VERSION 5.7 ;
BUSBITCHARS "[]" ;
DIVIDERCHAR "/" ;
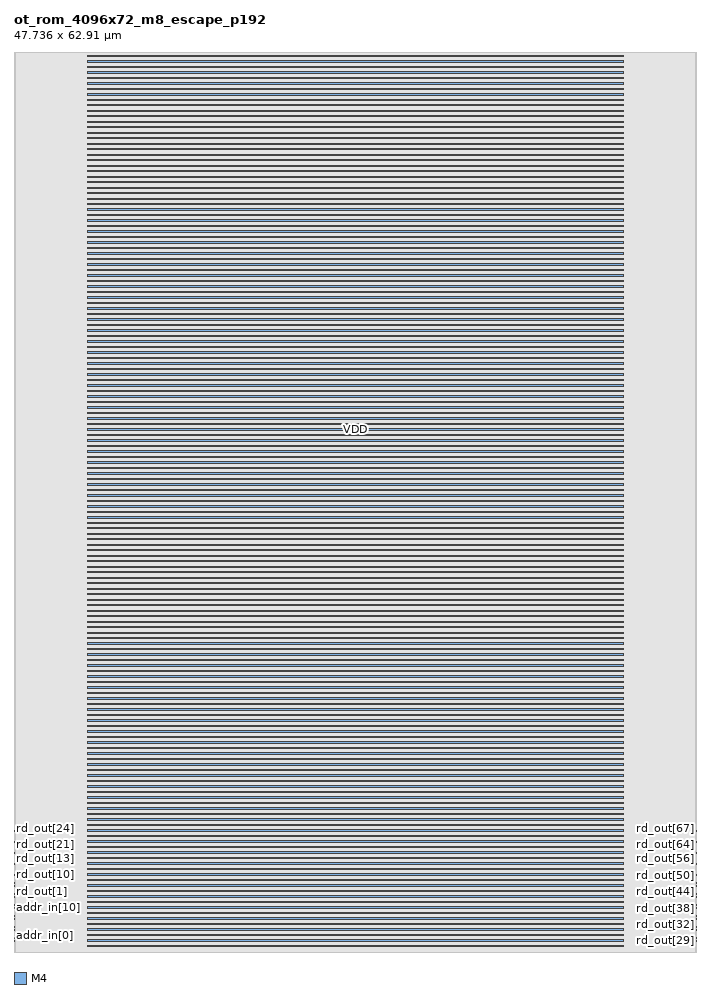
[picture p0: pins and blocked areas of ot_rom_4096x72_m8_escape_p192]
MACRO ot_rom_4096x72_m8_escape_p192
  SIZE 47.736 BY 62.910 ;
  CLASS BLOCK ;
  PIN clk
    DIRECTION INPUT ;
    USE CLOCK ;
    PORT
      LAYER M4 ;
      RECT 0.000 0.768 0.024 0.792 ;
    END
  END clk
  PIN ce_in
    DIRECTION INPUT ;
    USE SIGNAL ;
    PORT
      LAYER M4 ;
      RECT 0.000 0.960 0.024 0.984 ;
    END
  END ce_in
  PIN addr_in[0]
    DIRECTION INPUT ;
    USE SIGNAL ;
    PORT
      LAYER M4 ;
      RECT 0.000 1.152 0.024 1.176 ;
    END
  END addr_in[0]
  PIN addr_in[1]
    DIRECTION INPUT ;
    USE SIGNAL ;
    PORT
      LAYER M4 ;
      RECT 0.000 1.344 0.024 1.368 ;
    END
  END addr_in[1]
  PIN addr_in[2]
    DIRECTION INPUT ;
    USE SIGNAL ;
    PORT
      LAYER M4 ;
      RECT 0.000 1.536 0.024 1.560 ;
    END
  END addr_in[2]
  PIN addr_in[3]
    DIRECTION INPUT ;
    USE SIGNAL ;
    PORT
      LAYER M4 ;
      RECT 0.000 1.728 0.024 1.752 ;
    END
  END addr_in[3]
  PIN addr_in[4]
    DIRECTION INPUT ;
    USE SIGNAL ;
    PORT
      LAYER M4 ;
      RECT 0.000 1.920 0.024 1.944 ;
    END
  END addr_in[4]
  PIN addr_in[5]
    DIRECTION INPUT ;
    USE SIGNAL ;
    PORT
      LAYER M4 ;
      RECT 0.000 2.112 0.024 2.136 ;
    END
  END addr_in[5]
  PIN addr_in[6]
    DIRECTION INPUT ;
    USE SIGNAL ;
    PORT
      LAYER M4 ;
      RECT 0.000 2.304 0.024 2.328 ;
    END
  END addr_in[6]
  PIN addr_in[7]
    DIRECTION INPUT ;
    USE SIGNAL ;
    PORT
      LAYER M4 ;
      RECT 0.000 2.496 0.024 2.520 ;
    END
  END addr_in[7]
  PIN addr_in[8]
    DIRECTION INPUT ;
    USE SIGNAL ;
    PORT
      LAYER M4 ;
      RECT 0.000 2.688 0.024 2.712 ;
    END
  END addr_in[8]
  PIN addr_in[9]
    DIRECTION INPUT ;
    USE SIGNAL ;
    PORT
      LAYER M4 ;
      RECT 0.000 2.880 0.024 2.904 ;
    END
  END addr_in[9]
  PIN addr_in[10]
    DIRECTION INPUT ;
    USE SIGNAL ;
    PORT
      LAYER M4 ;
      RECT 0.000 3.072 0.024 3.096 ;
    END
  END addr_in[10]
  PIN addr_in[11]
    DIRECTION INPUT ;
    USE SIGNAL ;
    PORT
      LAYER M4 ;
      RECT 0.000 3.264 0.024 3.288 ;
    END
  END addr_in[11]
  PIN rd_out[0]
    DIRECTION OUTPUT ;
    USE SIGNAL ;
    PORT
      LAYER M4 ;
      RECT 0.000 3.456 0.024 3.480 ;
    END
  END rd_out[0]
  PIN rd_out[1]
    DIRECTION OUTPUT ;
    USE SIGNAL ;
    PORT
      LAYER M4 ;
      RECT 0.000 3.648 0.024 3.672 ;
    END
  END rd_out[1]
  PIN rd_out[2]
    DIRECTION OUTPUT ;
    USE SIGNAL ;
    PORT
      LAYER M4 ;
      RECT 0.000 3.840 0.024 3.864 ;
    END
  END rd_out[2]
  PIN rd_out[3]
    DIRECTION OUTPUT ;
    USE SIGNAL ;
    PORT
      LAYER M4 ;
      RECT 0.000 4.032 0.024 4.056 ;
    END
  END rd_out[3]
  PIN rd_out[4]
    DIRECTION OUTPUT ;
    USE SIGNAL ;
    PORT
      LAYER M4 ;
      RECT 0.000 4.224 0.024 4.248 ;
    END
  END rd_out[4]
  PIN rd_out[5]
    DIRECTION OUTPUT ;
    USE SIGNAL ;
    PORT
      LAYER M4 ;
      RECT 0.000 4.416 0.024 4.440 ;
    END
  END rd_out[5]
  PIN rd_out[6]
    DIRECTION OUTPUT ;
    USE SIGNAL ;
    PORT
      LAYER M4 ;
      RECT 0.000 4.608 0.024 4.632 ;
    END
  END rd_out[6]
  PIN rd_out[7]
    DIRECTION OUTPUT ;
    USE SIGNAL ;
    PORT
      LAYER M4 ;
      RECT 0.000 4.800 0.024 4.824 ;
    END
  END rd_out[7]
  PIN rd_out[8]
    DIRECTION OUTPUT ;
    USE SIGNAL ;
    PORT
      LAYER M4 ;
      RECT 0.000 4.992 0.024 5.016 ;
    END
  END rd_out[8]
  PIN rd_out[9]
    DIRECTION OUTPUT ;
    USE SIGNAL ;
    PORT
      LAYER M4 ;
      RECT 0.000 5.184 0.024 5.208 ;
    END
  END rd_out[9]
  PIN rd_out[10]
    DIRECTION OUTPUT ;
    USE SIGNAL ;
    PORT
      LAYER M4 ;
      RECT 0.000 5.376 0.024 5.400 ;
    END
  END rd_out[10]
  PIN rd_out[11]
    DIRECTION OUTPUT ;
    USE SIGNAL ;
    PORT
      LAYER M4 ;
      RECT 0.000 5.568 0.024 5.592 ;
    END
  END rd_out[11]
  PIN rd_out[12]
    DIRECTION OUTPUT ;
    USE SIGNAL ;
    PORT
      LAYER M4 ;
      RECT 0.000 5.760 0.024 5.784 ;
    END
  END rd_out[12]
  PIN rd_out[13]
    DIRECTION OUTPUT ;
    USE SIGNAL ;
    PORT
      LAYER M4 ;
      RECT 0.000 5.952 0.024 5.976 ;
    END
  END rd_out[13]
  PIN rd_out[14]
    DIRECTION OUTPUT ;
    USE SIGNAL ;
    PORT
      LAYER M4 ;
      RECT 0.000 6.144 0.024 6.168 ;
    END
  END rd_out[14]
  PIN rd_out[15]
    DIRECTION OUTPUT ;
    USE SIGNAL ;
    PORT
      LAYER M4 ;
      RECT 0.000 6.336 0.024 6.360 ;
    END
  END rd_out[15]
  PIN rd_out[16]
    DIRECTION OUTPUT ;
    USE SIGNAL ;
    PORT
      LAYER M4 ;
      RECT 0.000 6.528 0.024 6.552 ;
    END
  END rd_out[16]
  PIN rd_out[17]
    DIRECTION OUTPUT ;
    USE SIGNAL ;
    PORT
      LAYER M4 ;
      RECT 0.000 6.720 0.024 6.744 ;
    END
  END rd_out[17]
  PIN rd_out[18]
    DIRECTION OUTPUT ;
    USE SIGNAL ;
    PORT
      LAYER M4 ;
      RECT 0.000 6.912 0.024 6.936 ;
    END
  END rd_out[18]
  PIN rd_out[19]
    DIRECTION OUTPUT ;
    USE SIGNAL ;
    PORT
      LAYER M4 ;
      RECT 0.000 7.104 0.024 7.128 ;
    END
  END rd_out[19]
  PIN rd_out[20]
    DIRECTION OUTPUT ;
    USE SIGNAL ;
    PORT
      LAYER M4 ;
      RECT 0.000 7.296 0.024 7.320 ;
    END
  END rd_out[20]
  PIN rd_out[21]
    DIRECTION OUTPUT ;
    USE SIGNAL ;
    PORT
      LAYER M4 ;
      RECT 0.000 7.488 0.024 7.512 ;
    END
  END rd_out[21]
  PIN rd_out[22]
    DIRECTION OUTPUT ;
    USE SIGNAL ;
    PORT
      LAYER M4 ;
      RECT 0.000 7.680 0.024 7.704 ;
    END
  END rd_out[22]
  PIN rd_out[23]
    DIRECTION OUTPUT ;
    USE SIGNAL ;
    PORT
      LAYER M4 ;
      RECT 0.000 7.872 0.024 7.896 ;
    END
  END rd_out[23]
  PIN rd_out[24]
    DIRECTION OUTPUT ;
    USE SIGNAL ;
    PORT
      LAYER M4 ;
      RECT 0.000 8.064 0.024 8.088 ;
    END
  END rd_out[24]
  PIN rd_out[25]
    DIRECTION OUTPUT ;
    USE SIGNAL ;
    PORT
      LAYER M4 ;
      RECT 0.000 8.256 0.024 8.280 ;
    END
  END rd_out[25]
  PIN rd_out[26]
    DIRECTION OUTPUT ;
    USE SIGNAL ;
    PORT
      LAYER M4 ;
      RECT 0.000 8.448 0.024 8.472 ;
    END
  END rd_out[26]
  PIN rd_out[27]
    DIRECTION OUTPUT ;
    USE SIGNAL ;
    PORT
      LAYER M4 ;
      RECT 0.000 8.640 0.024 8.664 ;
    END
  END rd_out[27]
  PIN rd_out[28]
    DIRECTION OUTPUT ;
    USE SIGNAL ;
    PORT
      LAYER M4 ;
      RECT 0.000 8.832 0.024 8.856 ;
    END
  END rd_out[28]
  PIN rd_out[29]
    DIRECTION OUTPUT ;
    USE SIGNAL ;
    PORT
      LAYER M4 ;
      RECT 47.712 0.768 47.736 0.792 ;
    END
  END rd_out[29]
  PIN rd_out[30]
    DIRECTION OUTPUT ;
    USE SIGNAL ;
    PORT
      LAYER M4 ;
      RECT 47.712 0.960 47.736 0.984 ;
    END
  END rd_out[30]
  PIN rd_out[31]
    DIRECTION OUTPUT ;
    USE SIGNAL ;
    PORT
      LAYER M4 ;
      RECT 47.712 1.152 47.736 1.176 ;
    END
  END rd_out[31]
  PIN rd_out[32]
    DIRECTION OUTPUT ;
    USE SIGNAL ;
    PORT
      LAYER M4 ;
      RECT 47.712 1.344 47.736 1.368 ;
    END
  END rd_out[32]
  PIN rd_out[33]
    DIRECTION OUTPUT ;
    USE SIGNAL ;
    PORT
      LAYER M4 ;
      RECT 47.712 1.536 47.736 1.560 ;
    END
  END rd_out[33]
  PIN rd_out[34]
    DIRECTION OUTPUT ;
    USE SIGNAL ;
    PORT
      LAYER M4 ;
      RECT 47.712 1.728 47.736 1.752 ;
    END
  END rd_out[34]
  PIN rd_out[35]
    DIRECTION OUTPUT ;
    USE SIGNAL ;
    PORT
      LAYER M4 ;
      RECT 47.712 1.920 47.736 1.944 ;
    END
  END rd_out[35]
  PIN rd_out[36]
    DIRECTION OUTPUT ;
    USE SIGNAL ;
    PORT
      LAYER M4 ;
      RECT 47.712 2.112 47.736 2.136 ;
    END
  END rd_out[36]
  PIN rd_out[37]
    DIRECTION OUTPUT ;
    USE SIGNAL ;
    PORT
      LAYER M4 ;
      RECT 47.712 2.304 47.736 2.328 ;
    END
  END rd_out[37]
  PIN rd_out[38]
    DIRECTION OUTPUT ;
    USE SIGNAL ;
    PORT
      LAYER M4 ;
      RECT 47.712 2.496 47.736 2.520 ;
    END
  END rd_out[38]
  PIN rd_out[39]
    DIRECTION OUTPUT ;
    USE SIGNAL ;
    PORT
      LAYER M4 ;
      RECT 47.712 2.688 47.736 2.712 ;
    END
  END rd_out[39]
  PIN rd_out[40]
    DIRECTION OUTPUT ;
    USE SIGNAL ;
    PORT
      LAYER M4 ;
      RECT 47.712 2.880 47.736 2.904 ;
    END
  END rd_out[40]
  PIN rd_out[41]
    DIRECTION OUTPUT ;
    USE SIGNAL ;
    PORT
      LAYER M4 ;
      RECT 47.712 3.072 47.736 3.096 ;
    END
  END rd_out[41]
  PIN rd_out[42]
    DIRECTION OUTPUT ;
    USE SIGNAL ;
    PORT
      LAYER M4 ;
      RECT 47.712 3.264 47.736 3.288 ;
    END
  END rd_out[42]
  PIN rd_out[43]
    DIRECTION OUTPUT ;
    USE SIGNAL ;
    PORT
      LAYER M4 ;
      RECT 47.712 3.456 47.736 3.480 ;
    END
  END rd_out[43]
  PIN rd_out[44]
    DIRECTION OUTPUT ;
    USE SIGNAL ;
    PORT
      LAYER M4 ;
      RECT 47.712 3.648 47.736 3.672 ;
    END
  END rd_out[44]
  PIN rd_out[45]
    DIRECTION OUTPUT ;
    USE SIGNAL ;
    PORT
      LAYER M4 ;
      RECT 47.712 3.840 47.736 3.864 ;
    END
  END rd_out[45]
  PIN rd_out[46]
    DIRECTION OUTPUT ;
    USE SIGNAL ;
    PORT
      LAYER M4 ;
      RECT 47.712 4.032 47.736 4.056 ;
    END
  END rd_out[46]
  PIN rd_out[47]
    DIRECTION OUTPUT ;
    USE SIGNAL ;
    PORT
      LAYER M4 ;
      RECT 47.712 4.224 47.736 4.248 ;
    END
  END rd_out[47]
  PIN rd_out[48]
    DIRECTION OUTPUT ;
    USE SIGNAL ;
    PORT
      LAYER M4 ;
      RECT 47.712 4.416 47.736 4.440 ;
    END
  END rd_out[48]
  PIN rd_out[49]
    DIRECTION OUTPUT ;
    USE SIGNAL ;
    PORT
      LAYER M4 ;
      RECT 47.712 4.608 47.736 4.632 ;
    END
  END rd_out[49]
  PIN rd_out[50]
    DIRECTION OUTPUT ;
    USE SIGNAL ;
    PORT
      LAYER M4 ;
      RECT 47.712 4.800 47.736 4.824 ;
    END
  END rd_out[50]
  PIN rd_out[51]
    DIRECTION OUTPUT ;
    USE SIGNAL ;
    PORT
      LAYER M4 ;
      RECT 47.712 4.992 47.736 5.016 ;
    END
  END rd_out[51]
  PIN rd_out[52]
    DIRECTION OUTPUT ;
    USE SIGNAL ;
    PORT
      LAYER M4 ;
      RECT 47.712 5.184 47.736 5.208 ;
    END
  END rd_out[52]
  PIN rd_out[53]
    DIRECTION OUTPUT ;
    USE SIGNAL ;
    PORT
      LAYER M4 ;
      RECT 47.712 5.376 47.736 5.400 ;
    END
  END rd_out[53]
  PIN rd_out[54]
    DIRECTION OUTPUT ;
    USE SIGNAL ;
    PORT
      LAYER M4 ;
      RECT 47.712 5.568 47.736 5.592 ;
    END
  END rd_out[54]
  PIN rd_out[55]
    DIRECTION OUTPUT ;
    USE SIGNAL ;
    PORT
      LAYER M4 ;
      RECT 47.712 5.760 47.736 5.784 ;
    END
  END rd_out[55]
  PIN rd_out[56]
    DIRECTION OUTPUT ;
    USE SIGNAL ;
    PORT
      LAYER M4 ;
      RECT 47.712 5.952 47.736 5.976 ;
    END
  END rd_out[56]
  PIN rd_out[57]
    DIRECTION OUTPUT ;
    USE SIGNAL ;
    PORT
      LAYER M4 ;
      RECT 47.712 6.144 47.736 6.168 ;
    END
  END rd_out[57]
  PIN rd_out[58]
    DIRECTION OUTPUT ;
    USE SIGNAL ;
    PORT
      LAYER M4 ;
      RECT 47.712 6.336 47.736 6.360 ;
    END
  END rd_out[58]
  PIN rd_out[59]
    DIRECTION OUTPUT ;
    USE SIGNAL ;
    PORT
      LAYER M4 ;
      RECT 47.712 6.528 47.736 6.552 ;
    END
  END rd_out[59]
  PIN rd_out[60]
    DIRECTION OUTPUT ;
    USE SIGNAL ;
    PORT
      LAYER M4 ;
      RECT 47.712 6.720 47.736 6.744 ;
    END
  END rd_out[60]
  PIN rd_out[61]
    DIRECTION OUTPUT ;
    USE SIGNAL ;
    PORT
      LAYER M4 ;
      RECT 47.712 6.912 47.736 6.936 ;
    END
  END rd_out[61]
  PIN rd_out[62]
    DIRECTION OUTPUT ;
    USE SIGNAL ;
    PORT
      LAYER M4 ;
      RECT 47.712 7.104 47.736 7.128 ;
    END
  END rd_out[62]
  PIN rd_out[63]
    DIRECTION OUTPUT ;
    USE SIGNAL ;
    PORT
      LAYER M4 ;
      RECT 47.712 7.296 47.736 7.320 ;
    END
  END rd_out[63]
  PIN rd_out[64]
    DIRECTION OUTPUT ;
    USE SIGNAL ;
    PORT
      LAYER M4 ;
      RECT 47.712 7.488 47.736 7.512 ;
    END
  END rd_out[64]
  PIN rd_out[65]
    DIRECTION OUTPUT ;
    USE SIGNAL ;
    PORT
      LAYER M4 ;
      RECT 47.712 7.680 47.736 7.704 ;
    END
  END rd_out[65]
  PIN rd_out[66]
    DIRECTION OUTPUT ;
    USE SIGNAL ;
    PORT
      LAYER M4 ;
      RECT 47.712 7.872 47.736 7.896 ;
    END
  END rd_out[66]
  PIN rd_out[67]
    DIRECTION OUTPUT ;
    USE SIGNAL ;
    PORT
      LAYER M4 ;
      RECT 47.712 8.064 47.736 8.088 ;
    END
  END rd_out[67]
  PIN rd_out[68]
    DIRECTION OUTPUT ;
    USE SIGNAL ;
    PORT
      LAYER M4 ;
      RECT 47.712 8.256 47.736 8.280 ;
    END
  END rd_out[68]
  PIN rd_out[69]
    DIRECTION OUTPUT ;
    USE SIGNAL ;
    PORT
      LAYER M4 ;
      RECT 47.712 8.448 47.736 8.472 ;
    END
  END rd_out[69]
  PIN rd_out[70]
    DIRECTION OUTPUT ;
    USE SIGNAL ;
    PORT
      LAYER M4 ;
      RECT 47.712 8.640 47.736 8.664 ;
    END
  END rd_out[70]
  PIN rd_out[71]
    DIRECTION OUTPUT ;
    USE SIGNAL ;
    PORT
      LAYER M4 ;
      RECT 47.712 8.832 47.736 8.856 ;
    END
  END rd_out[71]
  PIN VDD
    DIRECTION INOUT ;
    USE POWER ;
    PORT
      LAYER M4 ;
      RECT 5.160 0.384 42.576 0.480 ;
      RECT 5.160 1.152 42.576 1.248 ;
      RECT 5.160 1.920 42.576 2.016 ;
      RECT 5.160 2.688 42.576 2.784 ;
      RECT 5.160 3.456 42.576 3.552 ;
      RECT 5.160 4.224 42.576 4.320 ;
      RECT 5.160 4.992 42.576 5.088 ;
      RECT 5.160 5.760 42.576 5.856 ;
      RECT 5.160 6.528 42.576 6.624 ;
      RECT 5.160 7.296 42.576 7.392 ;
      RECT 5.160 8.064 42.576 8.160 ;
      RECT 5.160 8.832 42.576 8.928 ;
      RECT 5.160 9.600 42.576 9.696 ;
      RECT 5.160 10.368 42.576 10.464 ;
      RECT 5.160 11.136 42.576 11.232 ;
      RECT 5.160 11.904 42.576 12.000 ;
      RECT 5.160 12.672 42.576 12.768 ;
      RECT 5.160 13.440 42.576 13.536 ;
      RECT 5.160 14.208 42.576 14.304 ;
      RECT 5.160 14.976 42.576 15.072 ;
      RECT 5.160 15.744 42.576 15.840 ;
      RECT 5.160 16.512 42.576 16.608 ;
      RECT 5.160 17.280 42.576 17.376 ;
      RECT 5.160 18.048 42.576 18.144 ;
      RECT 5.160 18.816 42.576 18.912 ;
      RECT 5.160 19.584 42.576 19.680 ;
      RECT 5.160 20.352 42.576 20.448 ;
      RECT 5.160 21.120 42.576 21.216 ;
      RECT 5.160 21.888 42.576 21.984 ;
      RECT 5.160 22.656 42.576 22.752 ;
      RECT 5.160 23.424 42.576 23.520 ;
      RECT 5.160 24.192 42.576 24.288 ;
      RECT 5.160 24.960 42.576 25.056 ;
      RECT 5.160 25.728 42.576 25.824 ;
      RECT 5.160 26.496 42.576 26.592 ;
      RECT 5.160 27.264 42.576 27.360 ;
      RECT 5.160 28.032 42.576 28.128 ;
      RECT 5.160 28.800 42.576 28.896 ;
      RECT 5.160 29.568 42.576 29.664 ;
      RECT 5.160 30.336 42.576 30.432 ;
      RECT 5.160 31.104 42.576 31.200 ;
      RECT 5.160 31.872 42.576 31.968 ;
      RECT 5.160 32.640 42.576 32.736 ;
      RECT 5.160 33.408 42.576 33.504 ;
      RECT 5.160 34.176 42.576 34.272 ;
      RECT 5.160 34.944 42.576 35.040 ;
      RECT 5.160 35.712 42.576 35.808 ;
      RECT 5.160 36.480 42.576 36.576 ;
      RECT 5.160 37.248 42.576 37.344 ;
      RECT 5.160 38.016 42.576 38.112 ;
      RECT 5.160 38.784 42.576 38.880 ;
      RECT 5.160 39.552 42.576 39.648 ;
      RECT 5.160 40.320 42.576 40.416 ;
      RECT 5.160 41.088 42.576 41.184 ;
      RECT 5.160 41.856 42.576 41.952 ;
      RECT 5.160 42.624 42.576 42.720 ;
      RECT 5.160 43.392 42.576 43.488 ;
      RECT 5.160 44.160 42.576 44.256 ;
      RECT 5.160 44.928 42.576 45.024 ;
      RECT 5.160 45.696 42.576 45.792 ;
      RECT 5.160 46.464 42.576 46.560 ;
      RECT 5.160 47.232 42.576 47.328 ;
      RECT 5.160 48.000 42.576 48.096 ;
      RECT 5.160 48.768 42.576 48.864 ;
      RECT 5.160 49.536 42.576 49.632 ;
      RECT 5.160 50.304 42.576 50.400 ;
      RECT 5.160 51.072 42.576 51.168 ;
      RECT 5.160 51.840 42.576 51.936 ;
      RECT 5.160 52.608 42.576 52.704 ;
      RECT 5.160 53.376 42.576 53.472 ;
      RECT 5.160 54.144 42.576 54.240 ;
      RECT 5.160 54.912 42.576 55.008 ;
      RECT 5.160 55.680 42.576 55.776 ;
      RECT 5.160 56.448 42.576 56.544 ;
      RECT 5.160 57.216 42.576 57.312 ;
      RECT 5.160 57.984 42.576 58.080 ;
      RECT 5.160 58.752 42.576 58.848 ;
      RECT 5.160 59.520 42.576 59.616 ;
      RECT 5.160 60.288 42.576 60.384 ;
      RECT 5.160 61.056 42.576 61.152 ;
      RECT 5.160 61.824 42.576 61.920 ;
      RECT 5.160 62.592 42.576 62.688 ;
    END
  END VDD
  PIN VSS
    DIRECTION INOUT ;
    USE GROUND ;
    PORT
      LAYER M4 ;
      RECT 5.160 0.768 42.576 0.864 ;
      RECT 5.160 1.536 42.576 1.632 ;
      RECT 5.160 2.304 42.576 2.400 ;
      RECT 5.160 3.072 42.576 3.168 ;
      RECT 5.160 3.840 42.576 3.936 ;
      RECT 5.160 4.608 42.576 4.704 ;
      RECT 5.160 5.376 42.576 5.472 ;
      RECT 5.160 6.144 42.576 6.240 ;
      RECT 5.160 6.912 42.576 7.008 ;
      RECT 5.160 7.680 42.576 7.776 ;
      RECT 5.160 8.448 42.576 8.544 ;
      RECT 5.160 9.216 42.576 9.312 ;
      RECT 5.160 9.984 42.576 10.080 ;
      RECT 5.160 10.752 42.576 10.848 ;
      RECT 5.160 11.520 42.576 11.616 ;
      RECT 5.160 12.288 42.576 12.384 ;
      RECT 5.160 13.056 42.576 13.152 ;
      RECT 5.160 13.824 42.576 13.920 ;
      RECT 5.160 14.592 42.576 14.688 ;
      RECT 5.160 15.360 42.576 15.456 ;
      RECT 5.160 16.128 42.576 16.224 ;
      RECT 5.160 16.896 42.576 16.992 ;
      RECT 5.160 17.664 42.576 17.760 ;
      RECT 5.160 18.432 42.576 18.528 ;
      RECT 5.160 19.200 42.576 19.296 ;
      RECT 5.160 19.968 42.576 20.064 ;
      RECT 5.160 20.736 42.576 20.832 ;
      RECT 5.160 21.504 42.576 21.600 ;
      RECT 5.160 22.272 42.576 22.368 ;
      RECT 5.160 23.040 42.576 23.136 ;
      RECT 5.160 23.808 42.576 23.904 ;
      RECT 5.160 24.576 42.576 24.672 ;
      RECT 5.160 25.344 42.576 25.440 ;
      RECT 5.160 26.112 42.576 26.208 ;
      RECT 5.160 26.880 42.576 26.976 ;
      RECT 5.160 27.648 42.576 27.744 ;
      RECT 5.160 28.416 42.576 28.512 ;
      RECT 5.160 29.184 42.576 29.280 ;
      RECT 5.160 29.952 42.576 30.048 ;
      RECT 5.160 30.720 42.576 30.816 ;
      RECT 5.160 31.488 42.576 31.584 ;
      RECT 5.160 32.256 42.576 32.352 ;
      RECT 5.160 33.024 42.576 33.120 ;
      RECT 5.160 33.792 42.576 33.888 ;
      RECT 5.160 34.560 42.576 34.656 ;
      RECT 5.160 35.328 42.576 35.424 ;
      RECT 5.160 36.096 42.576 36.192 ;
      RECT 5.160 36.864 42.576 36.960 ;
      RECT 5.160 37.632 42.576 37.728 ;
      RECT 5.160 38.400 42.576 38.496 ;
      RECT 5.160 39.168 42.576 39.264 ;
      RECT 5.160 39.936 42.576 40.032 ;
      RECT 5.160 40.704 42.576 40.800 ;
      RECT 5.160 41.472 42.576 41.568 ;
      RECT 5.160 42.240 42.576 42.336 ;
      RECT 5.160 43.008 42.576 43.104 ;
      RECT 5.160 43.776 42.576 43.872 ;
      RECT 5.160 44.544 42.576 44.640 ;
      RECT 5.160 45.312 42.576 45.408 ;
      RECT 5.160 46.080 42.576 46.176 ;
      RECT 5.160 46.848 42.576 46.944 ;
      RECT 5.160 47.616 42.576 47.712 ;
      RECT 5.160 48.384 42.576 48.480 ;
      RECT 5.160 49.152 42.576 49.248 ;
      RECT 5.160 49.920 42.576 50.016 ;
      RECT 5.160 50.688 42.576 50.784 ;
      RECT 5.160 51.456 42.576 51.552 ;
      RECT 5.160 52.224 42.576 52.320 ;
      RECT 5.160 52.992 42.576 53.088 ;
      RECT 5.160 53.760 42.576 53.856 ;
      RECT 5.160 54.528 42.576 54.624 ;
      RECT 5.160 55.296 42.576 55.392 ;
      RECT 5.160 56.064 42.576 56.160 ;
      RECT 5.160 56.832 42.576 56.928 ;
      RECT 5.160 57.600 42.576 57.696 ;
      RECT 5.160 58.368 42.576 58.464 ;
      RECT 5.160 59.136 42.576 59.232 ;
      RECT 5.160 59.904 42.576 60.000 ;
      RECT 5.160 60.672 42.576 60.768 ;
      RECT 5.160 61.440 42.576 61.536 ;
      RECT 5.160 62.208 42.576 62.304 ;
    END
  END VSS
  OBS
    LAYER M1 ;
    RECT 0 0 47.736 62.910 ;
    LAYER M2 ;
    RECT 0 0 47.736 62.910 ;
    LAYER M3 ;
    RECT 0 0 47.736 62.910 ;
    LAYER M4 ;
    RECT 0.072 0 47.664 62.910 ;
  END
END ot_rom_4096x72_m8_escape_p192
END LIBRARY
